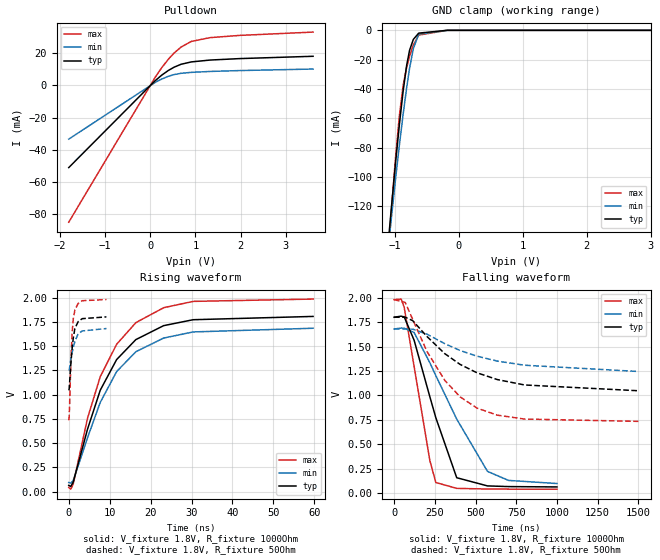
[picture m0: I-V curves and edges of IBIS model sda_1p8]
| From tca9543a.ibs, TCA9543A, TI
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|   sda_1p8 Model
[Model]   sda_1p8
Model_type   I/O_open_drain
Polarity   Non-Inverting
Vinl = 0.54
Vinh = 1.26
Vmeas = 0.9
Vref = 1.8
Cref = 50pF
Rref = 1000
|   typ   min   max
|   (nom PVT)   (fast PVT)   (slow PVT)
C_comp   3.839e-12   3.751e-12   3.993e-12
[Model spec]
|subparameter
Vinl   0.54   0.504   0.594
Vinh   1.26   1.176   1.386
| Where nom  PVT is Nominal Process, 1.8V, 27C
|   Fast PVT is Strong Process,  1.98V, -40C
|   Slow PVT is Weak Process,   1.68V, 85C
[Voltage Range]   1.8   1.68   1.98
|Junction Temperature
[Temperature Range]   27   85   -40
[Pullup Reference]   1.8   1.68   1.98
[Pulldown Reference]   0   0   0
[Power Clamp Reference]   1.8   1.68   1.98
[GND Clamp Reference]   0   0   0
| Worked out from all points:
|   slope of the pulldown table from 0 to 0.27 V, typ, clamps not added: 40.2 ohm
|   GND clamp passes 1 mA (typ) near -0.57 V on its own axis
|   falling waveform, V_fixture 1.8V, R_fixture 1000Ohm: 20-80 % time 179ns typ, 283ns min, 116ns max; typ from 1.8 V to 0.064 V
|   rising waveform, V_fixture 1.8V, R_fixture 1000Ohm: 20-80 % time 10.4ns typ, 10.8ns min, 10.1ns max; typ from 0.063 V to 1.81 V
|   falling waveform, V_fixture 1.8V, R_fixture 50Ohm: 20-80 % time 385ns typ, 461ns min, 281ns max; typ from 1.8 V to 1.05 V
|   rising waveform, V_fixture 1.8V, R_fixture 50Ohm: 20-80 % time 1.03ns typ, 1.48ns min, 715ps max; typ from 1.04 V to 1.8 V
[Pulldown]
|   Voltage   I(typ)   I(min)   I(max)
-1.8V     -51.13mA   -33.42mA   -85.13mA
106.8mV   2.876mA    1.819mA    4.918mA
251.3mV   6.325mA    3.935mA    10.92mA
402.5mV   9.347mA    5.686mA    16.35mA
526.8mV   11.34mA    6.739mA    20.12mA
682.2mV   13.18mA    7.554mA    23.89mA
909mV     14.65mA    8.139mA    27.41mA
1.328V    15.81mA    8.715mA    29.77mA
1.98V     16.71mA    9.259mA    31.15mA
3.6V      18.15mA    10.21mA    33.21mA
[GND Clamp]
|   Voltage   I(typ)   I(min)   I(max)
-1.8V     -545.8mA   -486.3mA   -651.9mA
-1.125V   -157.3mA   -159mA     -167.3mA
-1.059V   -124.9mA   -131.3mA   -127.7mA
-986.4mV  -90.6mA    -101.6mA   -87.03mA
-925.2mV  -64.03mA   -78.11mA   -57.89mA
-867.4mV  -41.55mA   -57.31mA   -37.68mA
-813.8mV  -24.32mA   -39.64mA   -25.54mA
-766.8mV  -13.6mA    -25.94mA   -17.69mA
-708mV    -6.218mA   -12.45mA   -10.06mA
-624mV    -1.916mA   -2.647mA   -3.249mA
-180mV    -31.47nA   -66.41nA   0A
3.6V      0A         0A         0A
[POWER Clamp]
|   Voltage   I(typ)   I(min)   I(max)
-1.8V     0A         0A         0A
-1.619V   0A         0A         0A
3.6V      0A         0A         0A
[Ramp]
R_load = 1000
|   typ   min   max
dV/dt_r   1.04202/1.02641e-08   0.952479/1.07255e-08   1.16334/1.00792e-08
dV/dt_f   1.04163/1.79323e-07   0.948733/2.82801e-07   1.16331/1.15229e-07
[Falling Waveform]
V_fixture = 1.8V
V_fixture_min = 1.68V
V_fixture_max = 1.98V
R_fixture = 1000Ohm
|   Time   V(typ)   V(min)   V(max)
0s        1.8V       1.68V      1.98V
43.7ns    1.811V     1.689V     1.986V
62.1ns    1.804V     1.688V     1.904V
123.1ns   1.565V     1.644V     1.296V
219.9ns   985.4mV    1.334V     332.4mV
256.4ns   772.2mV    1.203V     109.3mV
384.6ns   158.3mV    758.2mV    49.34mV
573.5ns   74.45mV    223.1mV    42.56mV
702.6ns   67.64mV    130.7mV    41.61mV
999.9ns   63.94mV    98.78mV    41.14mV
[Rising Waveform]
V_fixture = 1.8V
V_fixture_min = 1.68V
V_fixture_max = 1.98V
R_fixture = 1000Ohm
|   Time   V(typ)   V(min)   V(max)
0s        63.29mV    92.52mV    41.09mV
500ps     52.44mV    86.44mV    24.08mV
1.1ns     98.01mV    113.3mV    76.97mV
4.6ns     644.4mV    556.1mV    757.4mV
7.7ns     1.045V     919.3mV    1.185V
11.7ns    1.361V     1.237V     1.519V
16.4ns    1.567V     1.442V     1.742V
23.2ns    1.711V     1.583V     1.896V
30.4ns    1.772V     1.646V     1.961V
59.7ns    1.806V     1.684V     1.985V
[Falling Waveform]
V_fixture = 1.8V
V_fixture_min = 1.68V
V_fixture_max = 1.98V
R_fixture = 50Ohm
|   Time   V(typ)   V(min)   V(max)
0s        1.8V       1.68V      1.98V
68.8ns    1.8V       1.68V      1.951V
114.6ns   1.765V     1.678V     1.777V
202.1ns   1.603V     1.627V     1.45V
311ns     1.428V     1.53V      1.155V
405ns     1.318V     1.46V      986.2mV
508.7ns   1.232V     1.402V     870.8mV
634.7ns   1.162V     1.351V     798.1mV
801.8ns   1.107V     1.309V     758.2mV
1.5us     1.048V     1.245V     734.9mV
[Rising Waveform]
V_fixture = 1.8V
V_fixture_min = 1.68V
V_fixture_max = 1.98V
R_fixture = 50Ohm
|   Time   V(typ)   V(min)   V(max)
0s        1.043V     1.249V     734.4mV
100ps     1.057V     1.25V      766.7mV
200ps     1.115V     1.274V     882.9mV
500ps     1.311V     1.36V      1.313V
800ps     1.463V     1.428V     1.622V
1.1ns     1.58V      1.484V     1.779V
1.5ns     1.682V     1.548V     1.872V
2.3ns     1.752V     1.627V     1.94V
3.3ns     1.783V     1.656V     1.968V
9.2ns     1.801V     1.681V     1.98V
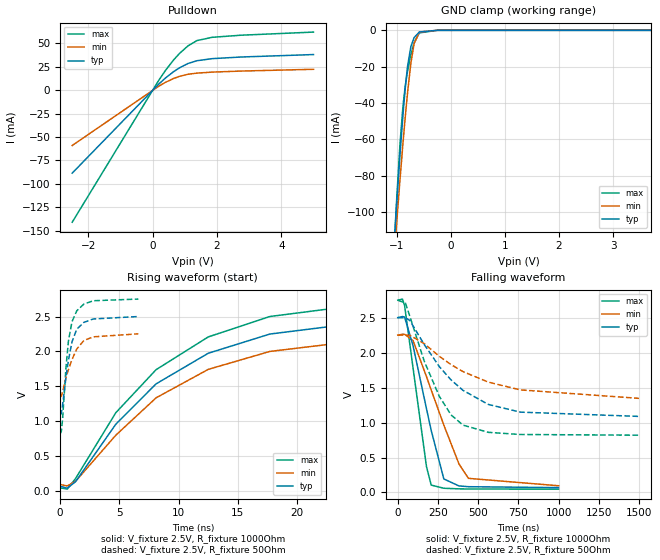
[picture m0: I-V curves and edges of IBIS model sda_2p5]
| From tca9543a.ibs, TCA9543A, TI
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|   sda_2p5 Model
[Model]   sda_2p5
Model_type   I/O_open_drain
Polarity   Non-Inverting
Vinl = 0.75
Vinh = 1.75
Vmeas = 1.25
Vref = 2.5
Cref = 50pF
Rref = 1000
|   typ   min   max
|   (nom PVT)   (fast PVT)   (slow PVT)
C_comp   3.751e-12   3.666e-12   3.961e-12
[Model spec]
|subparameter
Vinl   0.75   0.675   0.825
Vinh   1.75   1.575   1.925
| Where nom  PVT is Nominal Process, 2.5V, 27C
|   Fast PVT is Strong Process,  2.75V, -40C
|   Slow PVT is Weak Process,   2.25V, 85C
[Voltage Range]   2.5   2.25   2.75
|Junction Temperature
[Temperature Range]   27   85   -40
[Pullup Reference]   2.5   2.25   2.75
[Pulldown Reference]   0   0   0
[Power Clamp Reference]   2.5   2.25   2.75
[GND Clamp Reference]   0   0   0
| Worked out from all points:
|   slope of the pulldown table from 0 to 0.375 V, typ, clamps not added: 30.6 ohm
|   GND clamp passes 1 mA (typ) near -0.58 V on its own axis
|   falling waveform, V_fixture 2.5V, R_fixture 1000Ohm: 20-80 % time 138ns typ, 206ns min, 94.6ns max; typ from 2.5 V to 0.069 V
|   rising waveform, V_fixture 2.5V, R_fixture 1000Ohm: 20-80 % time 10.1ns typ, 10.4ns min, 9.86ns max; typ from 0.069 V to 2.5 V
|   falling waveform, V_fixture 2.5V, R_fixture 50Ohm: 20-80 % time 325ns typ, 445ns min, 206ns max; typ from 2.5 V to 1.09 V
|   rising waveform, V_fixture 2.5V, R_fixture 50Ohm: 20-80 % time 837ps typ, 1.19ns min, 635ps max; typ from 1.09 V to 2.5 V
[Pulldown]
|   Voltage   I(typ)   I(min)   I(max)
-2.5V     -88.53mA   -59.05mA   -140.9mA
192.5mV   6.59mA     4.295mA    10.65mA
401.2mV   13.05mA    8.397mA    21.16mA
652.2mV   19.77mA    12.47mA    32.26mA
836.7mV   23.89mA    14.78mA    39.23mA
1.1V      28.46mA    16.99mA    47.3mA
1.375V    31.42mA    18.19mA    52.88mA
1.849V    33.63mA    19.28mA    56.41mA
2.747V    35.39mA    20.39mA    58.66mA
5V        38.01mA    22.28mA    61.99mA
[GND Clamp]
|   Voltage   I(typ)   I(min)   I(max)
-2.5V     -1.006A    -874.2mA   -1.216A
-1.112V   -150.6mA   -153.3mA   -159.1mA
-1.004V   -98.63mA   -108.6mA   -96.38mA
-935.3mV  -68.23mA   -81.88mA   -62.22mA
-880.2mV  -46.26mA   -61.79mA   -41.44mA
-837.5mV  -31.38mA   -47.21mA   -30.32mA
-796.7mV  -19.89mA   -34.43mA   -22.49mA
-735mV    -8.915mA   -18.04mA   -13.28mA
-675.3mV  -4.003mA   -7.284mA   -6.822mA
-577.7mV  -903.1uA   -956.3uA   -1.426mA
-250mV    -312.2nA   -463.3nA   -125.1nA
5V        0A         0A         0A
[POWER Clamp]
|   Voltage   I(typ)   I(min)   I(max)
-2.5V     0A         0A         0A
-2.397V   0A         0A         0A
5V        0A         0A         0A
[Ramp]
R_load = 1000
|   typ   min   max
dV/dt_r   1.45855/1.00653e-08   1.29357/1.03726e-08   1.62156/9.86744e-09
dV/dt_f   1.45838/1.37563e-07   1.2923/2.05345e-07   1.62154/9.44721e-08
[Falling Waveform]
V_fixture = 2.5V
V_fixture_min = 2.25V
V_fixture_max = 2.75V
R_fixture = 1000Ohm
|   Time   V(typ)   V(min)   V(max)
0s        2.5V       2.25V      2.75V
29.3ns    2.516V     2.263V     2.766V
42.6ns    2.509V     2.262V     2.672V
95.4ns    2.097V     2.171V     1.776V
178.7ns   1.197V     1.657V     369.3mV
208ns     887.9mV    1.466V     105.6mV
286.6ns   193.1mV    963.3mV    60.41mV
380.8ns   93.72mV    407.5mV    51.85mV
439.6ns   82.62mV    202mV      49.97mV
999.9ns   69.37mV    96.16mV    47.43mV
[Rising Waveform]
V_fixture = 2.5V
V_fixture_min = 2.25V
V_fixture_max = 2.75V
R_fixture = 1000Ohm
|   Time   V(typ)   V(min)   V(max)
0s        69.07mV    94.04mV    47.4mV
600ps     42.17mV    73.96mV    27.64mV
1.3ns     134.4mV    140.6mV    179.9mV
4.7ns     958.1mV    800.8mV    1.123V
8.1ns     1.536V     1.336V     1.739V
12.5ns    1.974V     1.743V     2.208V
17.7ns    2.249V     2V         2.5V
26.8ns    2.442V     2.185V     2.698V
34.6ns    2.493V     2.238V     2.746V
69.9ns    2.5V       2.25V      2.75V
[Falling Waveform]
V_fixture = 2.5V
V_fixture_min = 2.25V
V_fixture_max = 2.75V
R_fixture = 50Ohm
|   Time   V(typ)   V(min)   V(max)
0s        2.5V       2.25V      2.75V
48.2ns    2.499V     2.251V     2.708V
74.8ns    2.46V      2.249V     2.521V
164ns     2.119V     2.129V     1.882V
258.8ns   1.799V     1.947V     1.373V
331.8ns   1.609V     1.828V     1.109V
406ns     1.46V      1.728V     963mV
563.3ns   1.259V     1.578V     860.2mV
762.2ns   1.149V     1.467V     829.3mV
1.5us     1.088V     1.346V     819.3mV
[Rising Waveform]
V_fixture = 2.5V
V_fixture_min = 2.25V
V_fixture_max = 2.75V
R_fixture = 50Ohm
|   Time   V(typ)   V(min)   V(max)
0s        1.086V     1.345V     819.2mV
100ps     1.114V     1.359V     856.2mV
200ps     1.225V     1.421V     1.016V
500ps     1.643V     1.628V     1.787V
700ps     1.877V     1.741V     2.151V
1ns       2.137V     1.884V     2.425V
1.4ns     2.318V     2.034V     2.581V
2ns       2.416V     2.156V     2.678V
2.8ns     2.465V     2.209V     2.726V
6.6ns     2.5V       2.252V     2.75V
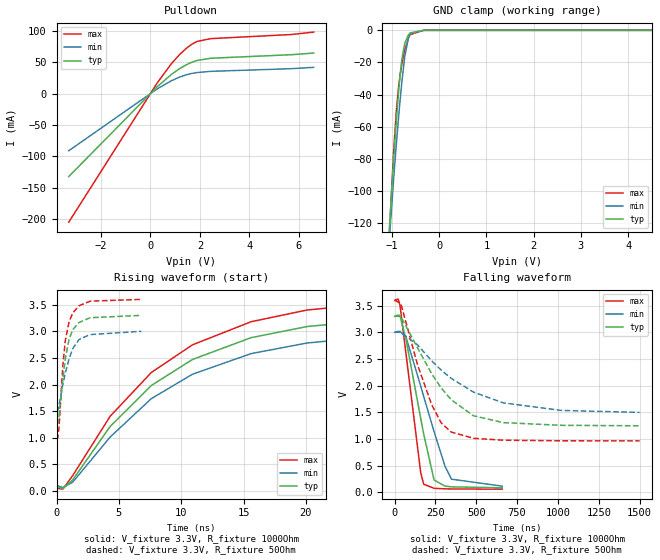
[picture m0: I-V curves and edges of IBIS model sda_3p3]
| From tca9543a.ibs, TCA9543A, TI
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|   sda_3p3 Model
[Model]   sda_3p3
Model_type   I/O_open_drain
Polarity   Non-Inverting
Vinl = 0.99
Vinh = 2.31
Vmeas = 1.65
Vref = 3.3
Cref = 50pF
Rref = 1000
|   typ   min   max
|   (nom PVT)   (fast PVT)   (slow PVT)
C_comp   3.694e-12   3.584e-12   3.930e-12
[Model spec]
|subparameter
Vinl   0.99   0.9   1.08
Vinh   2.31   2.1   2.52
| Where nom  PVT is Nominal Process, 3.3V, 27C
|   Fast PVT is Strong Process,  3.6V, -40C
|   Slow PVT is Weak Process,   3V, 85C
[Voltage Range]   3.3   3   3.6
|Junction Temperature
[Temperature Range]   27   85   -40
[Pullup Reference]   3.3   3   3.6
[Pulldown Reference]   0   0   0
[Power Clamp Reference]   3.3   3   3.6
[GND Clamp Reference]   0   0   0
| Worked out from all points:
|   slope of the pulldown table from 0 to 0.495 V, typ, clamps not added: 26.4 ohm
|   falling waveform, V_fixture 3.3V, R_fixture 1000Ohm: 20-80 % time 119ns typ, 168ns min, 84.7ns max; typ from 3.3 V to 0.082 V
|   rising waveform, V_fixture 3.3V, R_fixture 1000Ohm: 20-80 % time 9.96ns typ, 10.2ns min, 9.73ns max; typ from 0.08 V to 3.31 V
|   falling waveform, V_fixture 3.3V, R_fixture 50Ohm: 20-80 % time 261ns typ, 384ns min, 171ns max; typ from 3.3 V to 1.25 V
|   rising waveform, V_fixture 3.3V, R_fixture 50Ohm: 20-80 % time 747ps typ, 1.01ns min, 607ps max; typ from 1.25 V to 3.3 V
[Pulldown]
|   Voltage   I(typ)   I(min)   I(max)
-3.3V     -132.2mA   -91.1mA    -204.8mA
287.1mV   11.23mA    7.633mA    17.55mA
855mV     30.5mA     20.42mA    47.76mA
1.186V    39.63mA    26.19mA    62.18mA
1.452V    45.69mA    29.76mA    71.89mA
1.65V     49.34mA    31.71mA    77.82mA
1.884V    52.54mA    33.28mA    82.82mA
2.439V    56.11mA    35.26mA    87.34mA
5.696V    61.75mA    39.51mA    93.86mA
6.6V      64.37mA    41.59mA    97.73mA
[GND Clamp]
|   Voltage   I(typ)   I(min)   I(max)
-3.3V     -1.566A    -1.35A     -1.887A
-1.148V   -169.2mA   -169.1mA   -182mA
-963.6mV  -80.44mA   -92.71mA   -75.47mA
-902.4mV  -54.79mA   -69.72mA   -48.92mA
-861.3mV  -39.37mA   -55.2mA    -36.03mA
-831mV    -29.34mA   -45.09mA   -28.93mA
-788.7mV  -18.01mA   -32.06mA   -21.13mA
-726mV    -7.905mA   -16.05mA   -12.15mA
-646.8mV  -2.687mA   -4.248mA   -4.618mA
-612mV    -1.59mA    -2.042mA   -2.661mA
-330mV    -3.473uA   -3.656uA   -2.569uA
6.6V      0A         0A         0A
[POWER Clamp]
|   Voltage   I(typ)   I(min)   I(max)
-3.3V     0A         0A         0A
-3.183V   0A         0A         0A
6.6V      0A         0A         0A
[Ramp]
R_load = 1000
|   typ   min   max
dV/dt_r   1.93197/9.89045e-09   1.73653/1.0148e-08   2.1263/9.69268e-09
dV/dt_f   1.93186/1.18754e-07   1.73582/1.68044e-07   2.12629/8.46742e-08
[Falling Waveform]
V_fixture = 3.3V
V_fixture_min = 3V
V_fixture_max = 3.6V
R_fixture = 1000Ohm
|   Time   V(typ)   V(min)   V(max)
0s        3.3V       3V         3.6V
21.4ns    3.322V     3.018V     3.623V
32.4ns    3.313V     3.017V     3.509V
70.2ns    2.854V     2.901V     2.573V
159.4ns   1.384V     1.99V      366.8mV
177.6ns   1.092V     1.797V     149.5mV
241.3ns   228.5mV    1.136V     72.75mV
308.5ns   113.3mV    484.5mV    62.87mV
348.2ns   100.2mV    243.5mV    60.55mV
658.7ns   81.74mV    113.4mV    56.47mV
|   9.999e-07   0.0802309   0.106958   0.0561861
[Rising Waveform]
V_fixture = 3.3V
V_fixture_min = 3V
V_fixture_max = 3.6V
R_fixture = 1000Ohm
|   Time   V(typ)   V(min)   V(max)
0s        80.03mV    105.8mV    56.16mV
500ps     43.69mV    65.3mV     34.67mV
1.3ns     209.6mV    166.2mV    290.4mV
4.3ns     1.213V     1.014V     1.404V
7.6ns     1.982V     1.735V     2.226V
10.9ns    2.471V     2.194V     2.746V
15.6ns    2.881V     2.581V     3.18V
20.1ns    3.09V      2.781V     3.401V
26.3ns    3.227V     2.919V     3.537V
50ns      3.308V     3.008V     3.606V
[Falling Waveform]
V_fixture = 3.3V
V_fixture_min = 3V
V_fixture_max = 3.6V
R_fixture = 50Ohm
|   Time   V(typ)   V(min)   V(max)
0s        3.3V       3V         3.6V
37.1ns    3.298V     3.001V     3.544V
141ns     2.703V     2.76V      2.38V
226.7ns   2.22V      2.464V     1.64V
285.3ns   1.955V     2.289V     1.298V
345.9ns   1.735V     2.136V     1.128V
482.3ns   1.434V     1.878V     1.011V
665.3ns   1.305V     1.675V     974.8mV
1.023us   1.254V     1.533V     963.9mV
1.5us     1.246V     1.497V     963mV
[Rising Waveform]
V_fixture = 3.3V
V_fixture_min = 3V
V_fixture_max = 3.6V
R_fixture = 50Ohm
|   Time   V(typ)   V(min)   V(max)
0s        1.245V     1.491V     963mV
100ps     1.276V     1.514V     1.001V
200ps     1.418V     1.615V     1.199V
500ps     2.091V     1.994V     2.333V
700ps     2.475V     2.211V     2.821V
1ns       2.847V     2.477V     3.172V
1.3ns     3.029V     2.675V     3.345V
1.8ns     3.166V     2.846V     3.48V
2.7ns     3.256V     2.939V     3.567V
6.8ns     3.3V       3V         3.6V
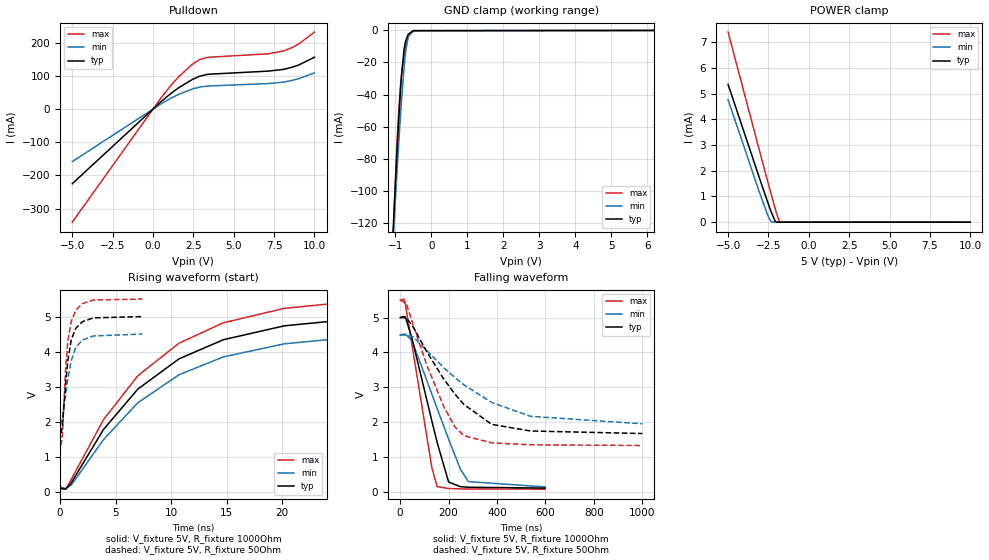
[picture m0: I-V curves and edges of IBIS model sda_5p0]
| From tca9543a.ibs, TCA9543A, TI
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|   sda_5p0 Model
[Model]   sda_5p0
Model_type   I/O_open_drain
Polarity   Non-Inverting
Vinl = 1.5
Vinh = 3.5
Vmeas = 2.5
Vref = 5
Cref = 50pF
Rref = 1000
|   typ   min   max
|   (nom PVT)   (fast PVT)   (slow PVT)
C_comp   3.638e-12   3.478e-12   3.899e-12
[Model spec]
|subparameter
Vinl   1.5   1.35   1.65
Vinh   3.5   3.15   3.85
| Where nom  PVT is Nominal Process, 5V, 27C
|   Fast PVT is Strong Process,  5.5V, -40C
|   Slow PVT is Weak Process,   4.5V, 85C
[Voltage Range]   5   4.5   5.5
|Junction Temperature
[Temperature Range]   27   85   -40
[Pullup Reference]   5   4.5   5.5
[Pulldown Reference]   0   0   0
[Power Clamp Reference]   5   4.5   5.5
[GND Clamp Reference]   0   0   0
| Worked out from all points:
|   slope of the pulldown table from 0 to 0.75 V, typ, clamps not added: 23 ohm
|   GND clamp passes 1 mA (typ) near -0.55 V on its own axis
|   POWER clamp passes 1 mA (typ) near -2.67 V on its own axis
|   falling waveform, V_fixture 5V, R_fixture 1000Ohm: 20-80 % time 103ns typ, 140ns min, 75.5ns max; typ from 5 V to 0.109 V
|   rising waveform, V_fixture 5V, R_fixture 1000Ohm: 20-80 % time 9.63ns typ, 9.9ns min, 9.41ns max; typ from 0.107 V to 5 V
|   falling waveform, V_fixture 5V, R_fixture 50Ohm: 20-80 % time 203ns typ, 290ns min, 141ns max; typ from 5 V to 1.67 V
|   rising waveform, V_fixture 5V, R_fixture 50Ohm: 20-80 % time 679ps typ, 875ps min, 577ps max; typ from 1.67 V to 5 V
[Pulldown]
|   Voltage   I(typ)   I(min)   I(max)
-5V       -225mA     -158.5mA   -340.9mA
503.5mV   22.29mA    15.58mA    33.94mA
1.129V    47.47mA    32.98mA    72.16mA
1.595V    64.13mA    44.28mA    97.37mA
2.452V    89.24mA    60.56mA    135.4mA
2.902V    98.79mA    66.04mA    149.2mA
3.404V    104.6mA    69.25mA    155.7mA
7.16V     114.1mA    76.57mA    166.2mA
8.1V      119.4mA    81.01mA    175mA
8.651V    126.2mA    86.36mA    185.7mA
9.04V     132.9mA    91.49mA    196.2mA
10V       155.9mA    108.8mA    231.6mA
[GND Clamp]
|   Voltage   I(typ)   I(min)   I(max)
-5V       -2.801A    -2.415A    -3.337A
-1.09V    -139.8mA   -144.1mA   -145.8mA
-1.04V    -115.5mA   -123.2mA   -116.4mA
-963.5mV  -80.4mA    -92.67mA   -75.42mA
-923mV    -63.12mA   -77.29mA   -56.98mA
-858.5mV  -38.39mA   -54.24mA   -35.29mA
-824mV    -27.23mA   -42.84mA   -27.51mA
-755mV    -11.64mA   -22.86mA   -15.98mA
-715.5mV  -6.873mA   -13.89mA   -10.9mA
-638.5mV  -2.382mA   -3.59mA    -4.08mA
-500mV    -209.9uA   -173.6uA   -275.6uA
10V       0A         0A         0A
[POWER Clamp]
|   Voltage   I(typ)   I(min)   I(max)
-5V       5.358mA    4.761mA    7.393mA
-3.042V   1.685mA    1.129mA    2.747mA
-2.494V   683.1uA    190.9uA    1.46mA
-2.327V   393.1uA    16.9uA     1.076mA
-2.09V    46.61uA    14.59nA    540.8uA
-2.02V    6.959uA    0A         388.8uA
-1.876V   32.47nA    0A         106.1uA
-1.788V   0A         0A         9.811uA
10V       0A         0A         0A
[Ramp]
R_load = 1000
|   typ   min   max
dV/dt_r   2.93556/9.60905e-09   2.61784/9.87438e-09   3.25325/9.41571e-09
dV/dt_f   2.93549/1.02627e-07   2.61742/1.3999e-07   3.25324/7.53339e-08
[Falling Waveform]
V_fixture = 5V
V_fixture_min = 4.5V
V_fixture_max = 5.5V
R_fixture = 1000Ohm
|   Time   V(typ)   V(min)   V(max)
0s        5V         4.5V       5.5V
15ns      5.032V     4.526V     5.531V
21.2ns    5.023V     4.527V     5.396V
48.4ns    4.413V     4.345V     4.232V
131ns     2.029V     2.802V     687.6mV
152.5ns   1.423V     2.394V     150.7mV
200ns     283mV      1.51V      97.99mV
248.4ns   150mV      655.2mV    87.01mV
281.5ns   133mV      295.1mV    83.88mV
598.4ns   109.1mV    143.4mV    78.25mV
[Rising Waveform]
V_fixture = 5V
V_fixture_min = 4.5V
V_fixture_max = 5.5V
R_fixture = 1000Ohm
|   Time   V(typ)   V(min)   V(max)
0s        107.4mV    136.9mV    77.91mV
500ps     72.71mV    90mV       73.48mV
1ns       252.1mV    187.8mV    351mV
3.9ns     1.775V     1.485V     2.055V
7ns       2.93V      2.541V     3.31V
10.7ns    3.791V     3.337V     4.238V
14.7ns    4.339V     3.849V     4.822V
20.2ns    4.736V     4.222V     5.235V
25.7ns    4.906V     4.388V     5.407V
52.2ns    5.005V     4.506V     5.499V
[Falling Waveform]
V_fixture = 5V
V_fixture_min = 4.5V
V_fixture_max = 5.5V
R_fixture = 50Ohm
|   Time   V(typ)   V(min)   V(max)
0s        5V         4.5V       5.5V
24.8ns    4.997V     4.501V     5.412V
53.9ns    4.727V     4.443V     4.79V
109.3ns   4.027V     4.057V     3.646V
179.3ns   3.244V     3.567V     2.456V
225.2ns   2.813V     3.283V     1.871V
262.8ns   2.51V      3.074V     1.612V
378ns     1.936V     2.565V     1.407V
538.1ns   1.747V     2.168V     1.35V
999.9ns   1.674V     1.953V     1.331V
[Rising Waveform]
V_fixture = 5V
V_fixture_min = 4.5V
V_fixture_max = 5.5V
R_fixture = 50Ohm
|   Time   V(typ)   V(min)   V(max)
0s        1.669V     1.93V      1.33V
100ps     1.698V     1.954V     1.362V
200ps     1.885V     2.09V      1.632V
500ps     3.106V     2.804V     3.558V
700ps     3.766V     3.244V     4.323V
1ns       4.334V     3.734V     4.861V
1.4ns     4.663V     4.115V     5.177V
2ns       4.854V     4.33V      5.37V
3ns       4.963V     4.447V     5.473V
7.4ns     5V         4.501V     5.5V
